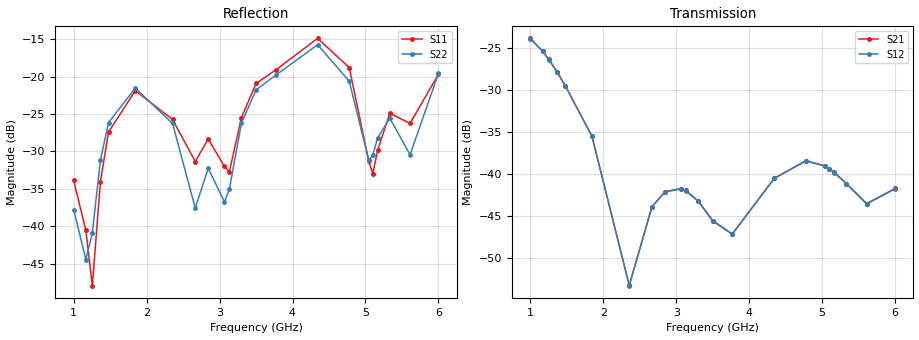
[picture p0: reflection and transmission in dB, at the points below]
!Agilent Technologies,E8364B,MY43040528,A.07.50.67
!Agilent E8364B: A.07.50.67
!Date: Sunday, March 01, 2026 16:42:49
!Correction: S11(Full 2 Port(1,2))
!S21(Full 2 Port(1,2))
!S12(Full 2 Port(1,2))
!S22(Full 2 Port(1,2))
!S2P File: Measurements: S11, S21, S12, S22:
# Hz S  dB  R 50
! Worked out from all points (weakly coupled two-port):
!   451 points, 1 GHz to 6 GHz, reference 50 ohm
!   highest |S21| = -23.87 dB at 1 GHz (marker M1); lowest = -53.3 dB at 2.356 GHz (marker M2)
!   lowest |S11| = -47.9 dB at 1.256 GHz (marker M3), VSWR 1.01, Z = 49.9 + j0.378 ohm
!   |S11| at or under -10 dB: start of sweep to end of sweep
!   |S22| runs from -44.6 to -15.6 dB; largest |S21 - S12| = 0.00028
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1e9  -33.88 31.9  -23.87 153.0  -23.90 153.0  -37.77 -14.6
1.166667e9  -40.55 48.8  -25.38 57.7  -25.42 57.7  -44.45 44.5
1.255556e9  -47.95 109.1  -26.38 7.2  -26.42 7.2  -40.90 106.3
1.366667e9  -34.03 166.1  -27.85 -55.1  -27.89 -55.0  -31.14 106.7
1.477778e9  -27.40 145.0  -29.48 -116.0  -29.51 -115.9  -26.13 81.0
1.844444e9  -21.87 75.7  -35.50 48.0  -35.53 48.1  -21.53 -7.5
2.355556e9  -25.72 12.5  -53.25 -148.9  -53.30 -148.9  -26.25 -108.7
2.666667e9  -31.34 35.8  -43.90 104.4  -43.94 104.4  -37.58 -92.3
2.844444e9  -28.34 33.8  -42.12 11.5  -42.15 11.5  -32.24 -95.3
3.066667e9  -32.00 29.6  -41.74 -106.8  -41.78 -106.8  -36.75 -99.0
3.133333e9  -32.74 52.5  -41.97 -142.2  -42.01 -142.2  -35.08 -72.5
3.3e9  -25.47 71.6  -43.20 131.6  -43.25 131.7  -26.21 -79.5
3.5e9  -20.90 47.2  -45.56 37.0  -45.60 37.1  -21.77 -120.1
3.766667e9  -19.12 21.8  -47.16 -65.8  -47.18 -65.9  -19.82 -161.1
4.344444e9  -14.87 -44.6  -40.51 23.1  -40.54 23.2  -15.72 100.2
4.777778e9  -18.78 -111.8  -38.42 140.7  -38.46 140.7  -20.61 14.3
5.044444e9  -31.27 -121.7  -39.05 -16.5  -39.10 -16.4  -31.15 14.2
5.1e9  -32.96 -87.3  -39.37 -49.8  -39.40 -49.9  -30.50 31.3
5.166667e9  -29.85 -60.5  -39.81 -90.2  -39.84 -90.2  -28.19 37.0
5.333333e9  -24.90 -67.4  -41.16 166.2  -41.19 166.2  -25.54 14.9
5.611111e9  -26.24 -71.0  -43.53 -22.4  -43.57 -22.4  -30.43 11.8
6e9  -19.68 -73.2  -41.73 60.1  -41.78 60.2  -19.56 -16.9
